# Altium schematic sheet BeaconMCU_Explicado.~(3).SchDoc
size A4

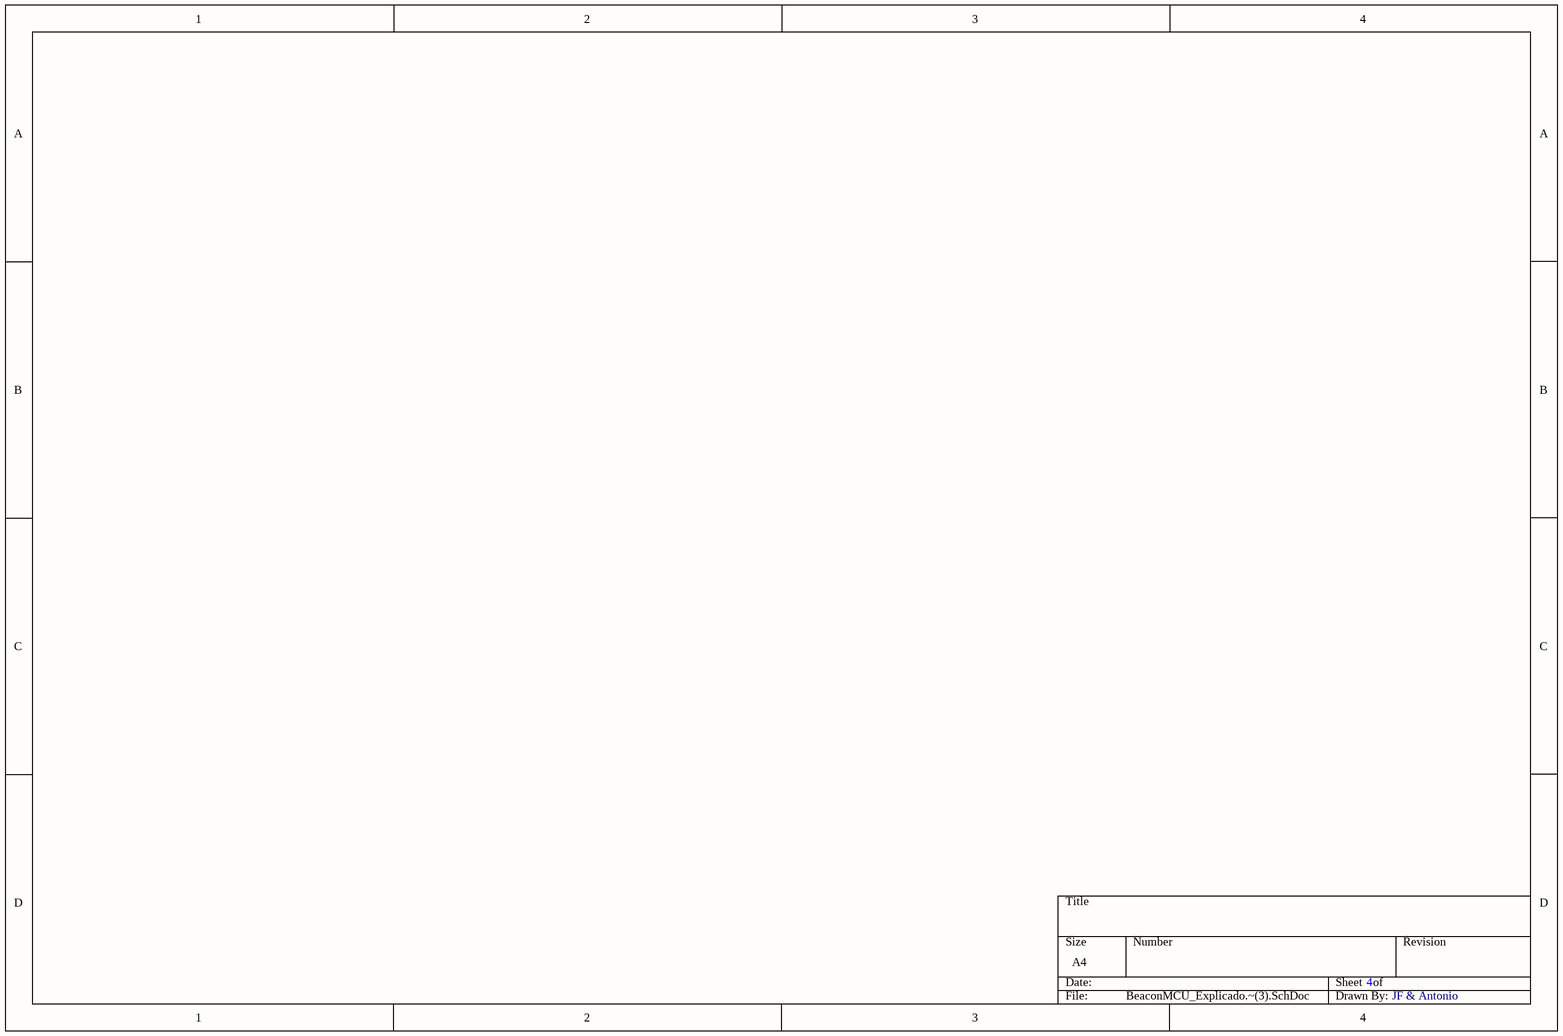
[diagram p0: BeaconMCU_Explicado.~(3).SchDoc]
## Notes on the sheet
- 4
- JF & Antonio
